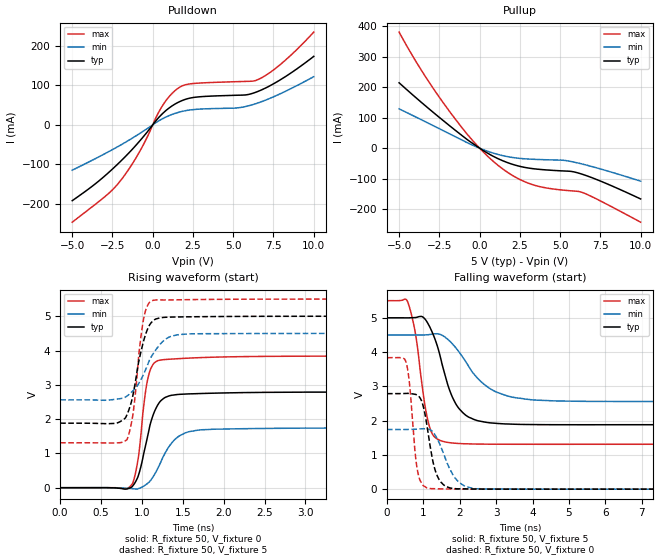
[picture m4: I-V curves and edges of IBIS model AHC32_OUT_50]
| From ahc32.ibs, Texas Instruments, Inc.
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[Model]   AHC32_OUT_50
Model_type  Output
|Vref =   0.0
|Rref =   1000
Cref =   50p
Vmeas =   2.5
| variable   typ   min   max
C_comp   2.57pF   1.60pF   3.54pF
| C_pullup   2.54pF   1.97pF   3.54pF
| C_pulldown   2.60pF   1.60pF   3.47pF
[Temperature Range]   40   100   -40
| Ambient temperature   25   85   -40
[Voltage range]   5   4.5   5.5
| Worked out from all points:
|   slope of the pulldown table from 0 to 0.75 V, typ, clamps not added: 22.2 ohm
|   slope of the pullup table from 0 to 0.75 V, typ, clamps not added: 31.3 ohm
|   rising waveform, R_fixture 50, V_fixture 0: 20-80 % time 174ps typ, 253ps min, 114ps max; typ from 0 V to 2.79 V
|   falling waveform, R_fixture 50, V_fixture 5: 20-80 % time 563ps typ, 909ps min, 333ps max; typ from 5 V to 1.88 V
|   rising waveform, R_fixture 50, V_fixture 5: 20-80 % time 161ps typ, 262ps min, 112ps max; typ from 1.88 V to 5 V
|   falling waveform, R_fixture 50, V_fixture 0: 20-80 % time 286ps typ, 440ps min, 186ps max; typ from 2.79 V to 0 V
[Pulldown]
| AHC32_OUT_50
|   Voltage   I(typ)   I(min)   I(max)
-5V       -191.8mA   -114.6mA   -246.2mA
-2.865V   -125.2mA   -70.62mA   -178mA
-2.005V   -92.58mA   -51.34mA   -141.4mA
-795mV    -40.14mA   -21.47mA   -66.35mA
560mV     26.51mA    14.37mA    45.43mA
1.005V    42.26mA    23.15mA    70.74mA
1.48V     54.77mA    30.23mA    89.72mA
2.385V    68.26mA    38.01mA    104mA
5.225V    74.86mA    42.83mA    109.2mA
6.5V      84.01mA    54.9mA     113.9mA
8.01V     116.1mA    80.32mA    155.5mA
10V       173.1mA    121.8mA    234.6mA
[Pullup]
| AHC32_OUT_50
|   Voltage   I(typ)   I(min)   I(max)
-5V       214.5mA    128.9mA    380.9mA
-3.485V   144.3mA    89.82mA    244.7mA
-1.79V    70.46mA    45.02mA    115.1mA
-235mV    8.419mA    5.273mA    13.4mA
495mV     -16.41mA   -10.12mA   -26.27mA
1.21V     -36.05mA   -21.63mA   -59.06mA
2.25V     -56.29mA   -32.15mA   -95.88mA
3.29V     -67.16mA   -36.41mA   -119.8mA
5.18V     -74.72mA   -39.75mA   -137.7mA
6.1V      -81.2mA    -48.6mA    -141.8mA
7.075V    -98.9mA    -61.83mA   -161.8mA
10V       -166.7mA   -108.3mA   -242.9mA
[Ramp]
| AHC32_OUT_50
| variable   typ   min   max
dV/dt_r   1.70/1.87E-10   1.07/2.69E-10   2.32/1.22E-10
dV/dt_f   1.90/5.83E-10   1.19/9.59E-10   2.54/3.45E-10
R_load = 50
[Rising Waveform]
| AHC32_OUT_50
R_fixture =   50
C_fixture =   0
L_fixture =   0
V_fixture =   0
V_fixture_min = 0
V_fixture_max = 0
|   Time   V(typ)   V(min)   V(max)
0s        -2.167uV   -16.21uV   2.82uV
850ps     -10.29mV   -22mV      23.65mV
935ps     230.3mV    -40.03mV   582.4mV
965ps     417.3mV    -20.29mV   1.03V
1.05ns    1.284V     90.19mV    2.889V
1.13ns    2.069V     292.8mV    3.57V
1.235ns   2.543V     769.6mV    3.726V
1.415ns   2.712V     1.432V     3.758V
1.795ns   2.751V     1.694V     3.8V
50ns      2.787V     1.74V      3.837V
[Falling Waveform]
| AHC32_OUT_50
R_fixture =   50
C_fixture =   0
L_fixture =   0
V_fixture =   5
V_fixture_min = 4.5
V_fixture_max = 5.5
|   Time   V(typ)   V(min)   V(max)
0s        5V         4.5V       5.5V
580ps     4.999V     4.5V       5.431V
790ps     5.008V     4.499V     4.478V
1.045ns   4.962V     4.5V       2.425V
1.28ns    4.481V     4.53V      1.554V
1.835ns   2.599V     4.193V     1.343V
2.22ns    2.116V     3.625V     1.322V
2.905ns   1.929V     2.886V     1.312V
4.595ns   1.881V     2.575V     1.309V
50ns      1.882V     2.562V     1.31V
[Rising Waveform]
| AHC32_OUT_50
R_fixture =   50
C_fixture =   0
L_fixture =   0
V_fixture =   5
V_fixture_min = 4.5
V_fixture_max = 5.5
|   Time   V(typ)   V(min)   V(max)
0s        1.882V     2.562V     1.31V
685ps     1.877V     2.579V     1.305V
815ps     2.115V     2.669V     1.394V
890ps     2.696V     2.823V     2.128V
970ps     3.77V      3.074V     4.043V
1.03ns    4.354V     3.357V     5.027V
1.185ns   4.93V      4.068V     5.476V
1.36ns    4.975V     4.416V     5.475V
1.75ns    4.987V     4.49V      5.489V
50ns      5V         4.5V       5.5V
[Falling Waveform]
| AHC32_OUT_50
R_fixture =   50
C_fixture =   0
L_fixture =   0
V_fixture =   0
V_fixture_min = 0
V_fixture_max = 0
|   Time   V(typ)   V(min)   V(max)
0s        2.787V     1.74V      3.837V
520ps     2.793V     1.741V     3.709V
615ps     2.792V     1.742V     3.103V
840ps     2.735V     1.752V     529.2mV
1.005ns   2.375V     1.763V     93.59mV
1.205ns   1.129V     1.718V     15.14mV
1.56ns    121.6mV    1.02V      6.46mV
1.925ns   10.72mV    257.1mV    2.47mV
2.46ns    3.567mV    10.73mV    545.5uV
50ns      -2.166uV   -16.21uV   2.82uV
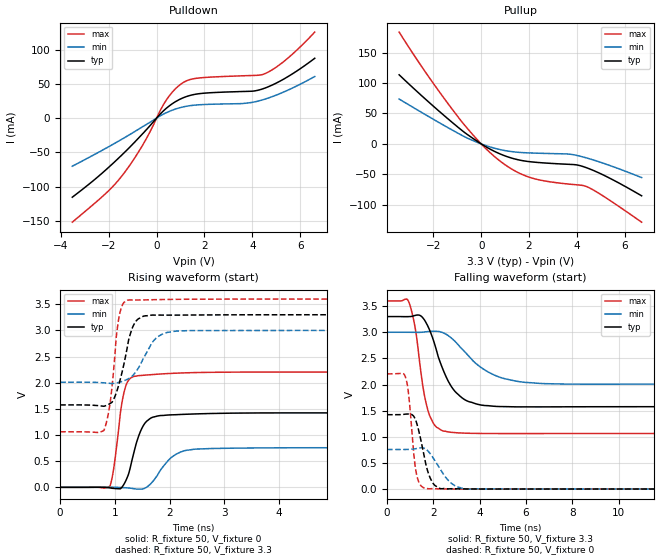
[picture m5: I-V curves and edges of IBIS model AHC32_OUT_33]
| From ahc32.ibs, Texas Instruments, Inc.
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[Model]   AHC32_OUT_33
Model_type  Output
|Vref =   0.0
|Rref =   1000
Cref =   50p
Vmeas =   1.65
| variable   typ   min   max
C_comp   2.74pF   1.71pF   4.14pF
| C_pullup   2.47pF   1.84pF   3.44pF
| C_pulldown   3.01pF   1.71pF   4.14pF
[Temperature Range]   40   100   -40
| Ambient temperature   25   85   -40
[Voltage range]   3.3   3   3.6
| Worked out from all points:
|   slope of the pulldown table from 0 to 0.495 V, typ, clamps not added: 29.4 ohm
|   slope of the pullup table from 0 to 0.495 V, typ, clamps not added: 44.5 ohm
|   rising waveform, R_fixture 50, V_fixture 0: 20-80 % time 239ps typ, 353ps min, 165ps max; typ from 0 V to 1.42 V
|   falling waveform, R_fixture 50, V_fixture 3.3: 20-80 % time 925ps typ, 1.52ns min, 515ps max; typ from 3.3 V to 1.58 V
|   rising waveform, R_fixture 50, V_fixture 3.3: 20-80 % time 228ps typ, 325ps min, 145ps max; typ from 1.58 V to 3.3 V
|   falling waveform, R_fixture 50, V_fixture 0: 20-80 % time 442ps typ, 701ps min, 272ps max; typ from 1.42 V to 0 V
[Pulldown]
| AHC32_OUT_33
|   Voltage   I(typ)   I(min)   I(max)
-3.525V   -115.6mA   -70.3mA    -152mA
-2.09V    -74.61mA   -43.5mA    -108.9mA
-1.505V   -55.66mA   -31.95mA   -86.88mA
-550mV    -21.61mA   -11.89mA   -37.48mA
360mV     12.89mA    7.06mA     23.79mA
955mV     27.12mA    14.92mA    47.99mA
1.225V    31.15mA    17.11mA    54.02mA
1.63V     34.84mA    19.02mA    57.91mA
3.605V    38.8mA     21.23mA    61.73mA
4.52V     43.69mA    27.57mA    64.75mA
5.475V    60.21mA    40.57mA    87.17mA
6.61V     87.31mA    60.67mA    125.5mA
[Pullup]
| AHC32_OUT_33
|   Voltage   I(typ)   I(min)   I(max)
-3.43V    113.4mA    73.61mA    183.6mA
-2.115V   65.93mA    43.05mA    105.7mA
-830mV    22.9mA     14.53mA    37.35mA
105mV     -2.578mA   -1.53mA    -4.254mA
800mV     -16.66mA   -9.429mA   -28.58mA
1.44V     -25.09mA   -13.41mA   -44.99mA
2.135V    -29.66mA   -14.98mA   -56.22mA
3.61V     -33.44mA   -16.56mA   -65.78mA
4.205V    -36.54mA   -20.91mA   -68mA
4.475V    -40.22mA   -23.86mA   -71.28mA
4.9V      -47.28mA   -29.07mA   -80.65mA
6.705V    -85.23mA   -55.27mA   -128.5mA
[Ramp]
| AHC32_OUT_33
| variable   typ   min   max
dV/dt_r   0.87/2.50E-10   0.47/3.84E-10   1.33/1.83E-10
dV/dt_f   1.05/9.85E-10   0.61/1.57E-09   1.54/5.37E-10
R_load = 50
[Rising Waveform]
| AHC32_OUT_33
R_fixture =   50
C_fixture =   0
L_fixture =   0
V_fixture =   0
V_fixture_min = 0
V_fixture_max = 0
|   Time   V(typ)   V(min)   V(max)
0s        -9.88uV    -20.89uV   -2.514uV
910ps     -10.92mV   2.15mV     23.89mV
990ps     -21.54mV   1.504mV    446.2mV
1.125ns   -957.1uV   -4.054mV   1.599V
1.23ns    202.1mV    -10.73mV   2.016V
1.415ns   924.2mV    -34.6mV    2.133V
1.55ns    1.229V     -14.1mV    2.146V
2.105ns   1.389V     626.3mV    2.183V
4.23ns    1.424V     756.8mV    2.204V
50ns      1.422V     756.2mV    2.203V
[Falling Waveform]
| AHC32_OUT_33
R_fixture =   50
C_fixture =   0
L_fixture =   0
V_fixture =   3.3
V_fixture_min = 3
V_fixture_max = 3.6
|   Time   V(typ)   V(min)   V(max)
0s        3.3V       3V         3.6V
925ps     3.299V     3V         3.594V
1.205ns   3.321V     2.998V     3.109V
1.55ns    3.275V     3.002V     1.962V
1.79ns    3.091V     3.014V     1.47V
2.73ns    1.995V     2.907V     1.087V
3.415ns   1.695V     2.598V     1.068V
4.535ns   1.587V     2.202V     1.062V
6.775ns   1.572V     2.017V     1.062V
50ns      1.576V     2.009V     1.062V
[Rising Waveform]
| AHC32_OUT_33
R_fixture =   50
C_fixture =   0
L_fixture =   0
V_fixture =   3.3
V_fixture_min = 3
V_fixture_max = 3.6
|   Time   V(typ)   V(min)   V(max)
0s        1.576V     2.009V     1.062V
800ps     1.551V     1.998V     1.091V
915ps     1.605V     1.988V     1.633V
1.025ns   1.808V     1.996V     2.88V
1.08ns    1.996V     2.01V      3.284V
1.28ns    2.928V     2.098V     3.585V
1.425ns   3.22V      2.276V     3.583V
1.775ns   3.293V     2.873V     3.59V
2.37ns    3.295V     2.998V     3.597V
50ns      3.3V       3V         3.6V
[Falling Waveform]
| AHC32_OUT_33
R_fixture =   50
C_fixture =   0
L_fixture =   0
V_fixture =   0
V_fixture_min = 0
V_fixture_max = 0
|   Time   V(typ)   V(min)   V(max)
0s        1.422V     756.2mV    2.203V
795ps     1.433V     756.3mV    2.144V
930ps     1.436V     757.5mV    1.819V
1.155ns   1.39V      765.9mV    672.4mV
1.275ns   1.268V     773.6mV    281.1mV
1.78ns    309.5mV    721.5mV    5.73mV
2.255ns   15.21mV    411mV      2.604mV
2.82ns    5.696mV    96.04mV    113.8uV
3.5ns     758.5uV    -3.08mV    -135.8uV
50ns      -9.881uV   -20.9uV    -2.513uV
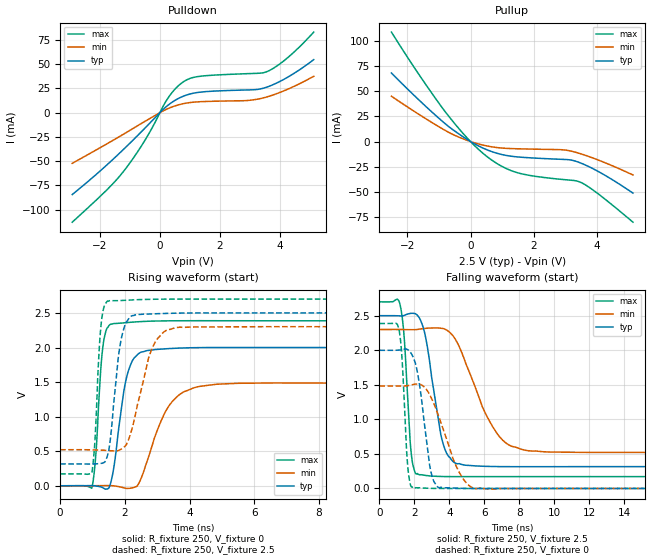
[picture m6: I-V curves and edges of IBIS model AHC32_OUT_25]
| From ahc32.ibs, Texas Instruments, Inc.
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[Model]   AHC32_OUT_25
Model_type  Output
|Vref =   0.0
|Rref =   1000
Cref =   50p
Vmeas =   1.25
| variable   typ   min   max
C_comp   2.69pF   1.57pF   4.56pF
| C_pullup   2.29pF   1.57pF   3.25pF
| C_pulldown   3.09pF   1.62pF   4.56pF
[Temperature Range]   40   100   -40
| Ambient temperature   25   85   -40
[Voltage range]   2.5   2.3   2.7
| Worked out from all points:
|   slope of the pulldown table from 0 to 0.375 V, typ, clamps not added: 37.2 ohm
|   slope of the pullup table from 0 to 0.375 V, typ, clamps not added: 59.9 ohm
|   rising waveform, R_fixture 250, V_fixture 0: 20-80 % time 369ps typ, 767ps min, 190ps max; typ from 0 V to 2 V
|   falling waveform, R_fixture 250, V_fixture 2.5: 20-80 % time 802ps typ, 1.78ns min, 346ps max; typ from 2.5 V to 0.316 V
|   rising waveform, R_fixture 250, V_fixture 2.5: 20-80 % time 294ps typ, 556ps min, 161ps max; typ from 0.316 V to 2.5 V
|   falling waveform, R_fixture 250, V_fixture 0: 20-80 % time 611ps typ, 1.26ns min, 287ps max; typ from 2 V to 0 V
[Pulldown]
| AHC32_OUT_25
|   Voltage   I(typ)   I(min)   I(max)
-2.925V   -84.52mA   -52.28mA   -113mA
-1.8V     -54.82mA   -32.75mA   -80.62mA
-1.205V   -37.64mA   -22.04mA   -60.28mA
-490mV    -15.69mA   -8.829mA   -28.09mA
265mV     7.52mA     4.123mA    14.76mA
685mV     15.66mA    8.561mA    29.57mA
965mV     18.91mA    10.25mA    34.83mA
1.295V    20.97mA    11.21mA    37.35mA
2.885V    23.41mA    12.43mA    40.19mA
3.535V    25.98mA    15.9mA     41.87mA
4.285V    36.92mA    24.43mA    57.2mA
5.135V    54.7mA     37.55mA    83.12mA
[Pullup]
| AHC32_OUT_25
|   Voltage   I(typ)   I(min)   I(max)
-2.5V     68.34mA    45.17mA    109.1mA
-1.595V   40.37mA    26.34mA    65.2mA
-805mV    17.87mA    11.17mA    29.92mA
-120mV    2.341mA    1.34mA     4.04mA
475mV     -7.653mA   -4.114mA   -13.84mA
985mV     -12.92mA   -6.478mA   -24.64mA
1.47V     -15.3mA    -7.208mA   -30.97mA
2.885V    -17.76mA   -8.179mA   -37.75mA
3.21V     -18.66mA   -9.781mA   -38.67mA
3.48V     -21.39mA   -12.2mA    -40.65mA
4.085V    -30.69mA   -19.02mA   -53.35mA
5.135V    -51.41mA   -33.33mA   -80.43mA
[Ramp]
| AHC32_OUT_25
| variable   typ   min   max
dV/dt_r   1.23/4.03E-10   0.92/8.12E-10   1.45/2.01E-10
dV/dt_f   1.33/8.61E-10   1.08/1.90E-09   1.54/3.56E-10
R_load = 250
[Rising Waveform]
| AHC32_OUT_25
R_fixture =   250
C_fixture =   0
L_fixture =   0
V_fixture =   0
V_fixture_min = 0
V_fixture_max = 0
|   Time   V(typ)   V(min)   V(max)
0s        -14.8uV    -30.31uV   -4.854uV
980ps     1.845mV    561uV      -34.07mV
1.105ns   -3.727mV   982uV      464.5mV
1.33ns    -32.2mV    2.312mV    2.044V
1.67ns    298mV      -2.34mV    2.347V
2.14ns    1.706V     -37.23mV   2.364V
3.03ns    1.974V     836.3mV    2.384V
3.79ns    1.993V     1.351V     2.387V
5.51ns    2.001V     1.483V     2.387V
50ns      1.999V     1.482V     2.386V
[Falling Waveform]
| AHC32_OUT_25
R_fixture =   250
C_fixture =   0
L_fixture =   0
V_fixture =   2.5
V_fixture_min = 2.3
V_fixture_max = 2.7
|   Time   V(typ)   V(min)   V(max)
0s        2.5V       2.3V       2.7V
1.185ns   2.497V     2.3V       2.658V
1.415ns   2.503V     2.299V     2.199V
1.835ns   2.534V     2.297V     481.5mV
2.29ns    2.467V     2.305V     198.8mV
3.665ns   630.7mV    2.312V     172.6mV
4.835ns   339.4mV    1.885V     171.2mV
6.735ns   316.8mV    793.5mV    171.3mV
8.535ns   315.2mV    545mV      171.5mV
50ns      315.9mV    521.1mV    171.6mV
[Rising Waveform]
| AHC32_OUT_25
R_fixture =   250
C_fixture =   0
L_fixture =   0
V_fixture =   2.5
V_fixture_min = 2.3
V_fixture_max = 2.7
|   Time   V(typ)   V(min)   V(max)
0s        315.9mV    521.1mV    171.6mV
980ps     313.6mV    519.5mV    186.6mV
1.07ns    315.6mV    518.5mV    614.2mV
1.27ns    324.1mV    515.4mV    2.354V
1.555ns   689.8mV    506.5mV    2.679V
1.9ns     2.15V      534mV      2.68V
2.395ns   2.479V     1.182V     2.692V
2.92ns    2.488V     2.063V     2.698V
3.69ns    2.497V     2.294V     2.701V
50ns      2.5V       2.3V       2.7V
[Falling Waveform]
| AHC32_OUT_25
R_fixture =   250
C_fixture =   0
L_fixture =   0
V_fixture =   0
V_fixture_min = 0
V_fixture_max = 0
|   Time   V(typ)   V(min)   V(max)
0s        1.999V     1.482V     2.386V
1.135ns   2.002V     1.482V     2.284V
1.3ns     2.007V     1.482V     1.863V
1.63ns    2.007V     1.488V     301.7mV
1.975ns   1.872V     1.506V     -550.1uV
2.91ns    290.3mV    1.341V     2.15mV
3.415ns   11.52mV    1.026V     281.1uV
4.53ns    3.322mV    250.9mV    -329.8uV
5.51ns    -150.7uV   -1.446mV   -181.9uV
50ns      -14.81uV   -30.35uV   -4.854uV
